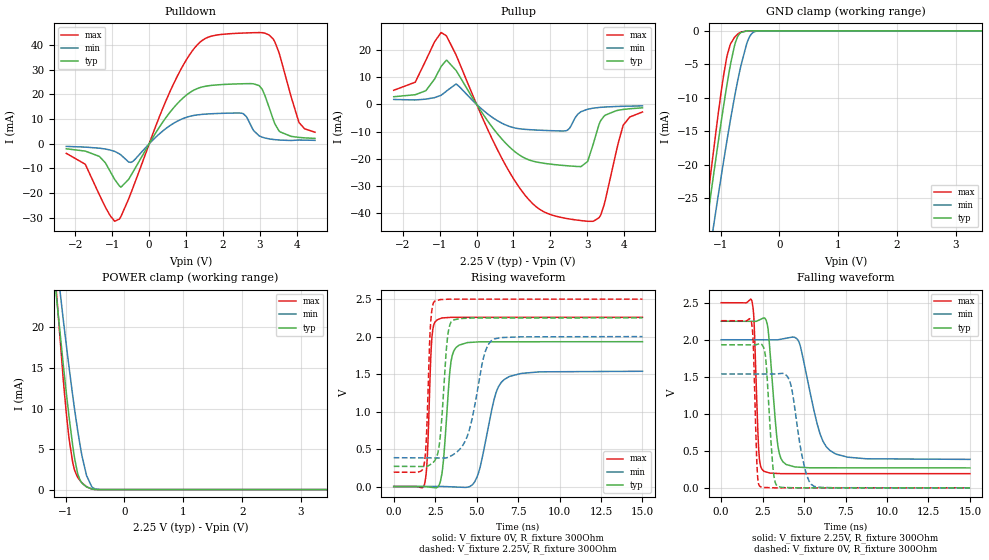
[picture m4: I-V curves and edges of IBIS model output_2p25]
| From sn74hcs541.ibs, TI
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|   output_2p25 Model
[Model]   output_2p25
Model_type   I/O
Polarity   Non-Inverting
Enable   Active-High
Vmeas = 1.125
Vref = 0
Cref = 2pF
Rref = 100000
Vinl = 0.835
Vinh = 1.2
|   typ   min   max
C_comp   0.937pF   0.886pF   0.963pF
| Where Nom  PVT is Nominal Process, 2.25V, 27C
|   Fast PVT is Strong Process,  2.50V, -55C
|   Slow PVT is Weak Process,   2.0V, 150C
[Voltage Range]   2.25   2   2.5
|Junction Temperature
[Temperature Range]   27   150   -55
[Pullup Reference]   2.25   2   2.5
[Pulldown Reference]   0   0   0
[Power Clamp Reference]   2.25   2   2.5
[GND Clamp Reference]   0   0   0
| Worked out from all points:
|   slope of the pulldown table from 0 to 0.337 V, typ, clamps not added: 41.6 ohm
|   slope of the pullup table from 0 to 0.337 V, typ, clamps not added: 49.5 ohm
|   GND clamp passes 1 mA (typ) near -0.72 V on its own axis
|   POWER clamp passes 1 mA (typ) near -0.74 V on its own axis
|   falling waveform, V_fixture 2.25V, R_fixture 300Ohm: 20-80 % time 427ps typ, 992ps min, 216ps max; typ from 2.25 V to 0.269 V
|   rising waveform, V_fixture 0V, R_fixture 300Ohm: 20-80 % time 377ps typ, 879ps min, 215ps max; typ from 0 V to 1.93 V
|   rising waveform, V_fixture 2.25V, R_fixture 300Ohm: 20-80 % time 379ps typ, 878ps min, 218ps max; typ from 0.269 V to 2.25 V
|   falling waveform, V_fixture 0V, R_fixture 300Ohm: 20-80 % time 325ps typ, 662ps min, 177ps max; typ from 1.93 V to 0 V
[Pulldown]
|   Voltage   I(typ)   I(min)   I(max)
-2.25V    -2.019mA   -1.051mA   -3.867mA
-1.737V   -2.956mA   -1.338mA   -8.261mA
-1.352V   -5.109mA   -1.777mA   -20.65mA
-805.5mV  -17.13mA   -4.093mA   -30.48mA
-461.2mV  -11.99mA   -7.313mA   -18.63mA
949.5mV   18.99mA    10.42mA    32.57mA
2.057V    24.09mA    12.39mA    44.49mA
2.556V    24.35mA    12.19mA    44.91mA
2.981V    23.61mA    3.258mA    45.1mA
3.359V    10.14mA    1.771mA    42.63mA
4.061V    2.596mA    1.53mA     8.818mA
4.5V      2.197mA    1.398mA    4.702mA
[GND Clamp]
|   Voltage   I(typ)   I(min)   I(max)
-2.25V    -97.51mA   -98.31mA   -106.7mA
-1.413V   -40.56mA   -46.57mA   -39.9mA
-1.17V    -24.74mA   -32.11mA   -21.56mA
-1.157V   -23.88mA   -31.32mA   -20.58mA
-1.048V   -17.16mA   -25.09mA   -13.01mA
-954mV    -11.56mA   -19.8mA    -7.02mA
-886.5mV  -7.821mA   -16.15mA   -3.647mA
-758.2mV  -2.094mA   -9.706mA   -933.8uA
-650.2mV  -236.3uA   -5.079mA   -178.5uA
-515.2mV  -9.553uA   -1.047mA   -5.579uA
-373.5mV  -159.7nA   -38.68uA   -18.72nA
4.5V      0A         0A         0A
[Pullup]
|   Voltage   I(typ)   I(min)   I(max)
-2.25V    2.824mA    1.819mA    5.194mA
-1.669V   3.557mA    1.632mA    8.15mA
-1.379V   5.027mA    1.94mA     16.19mA
-825.7mV  16.2mA     4.794mA    25.31mA
-555.7mV  12.46mA    7.533mA    18.14mA
463.5mV   -9.106mA   -5.134mA   -13.92mA
1.253V    -19.4mA    -9.115mA   -32.38mA
2.434V    -22.56mA   -9.668mA   -41.98mA
3.015V    -20.85mA   -1.762mA   -43.03mA
3.454V    -4.395mA   -992.6uA   -37.21mA
3.974V    -1.87mA    -692.2uA   -7.807mA
4.5V      -1.267mA   -550uA     -2.795mA
[POWER Clamp]
|   Voltage   I(typ)   I(min)   I(max)
-2.25V    111.3mA    101.8mA    143.6mA
-1.305V   34.66mA    37.92mA    38.3mA
-1.042V   15.57mA    21.11mA    13.76mA
-987.8mV  11.94mA    17.84mA    9.441mA
-940.5mV  8.946mA    15.06mA    6.255mA
-879.8mV  5.467mA    11.64mA    3.383mA
-792mV    1.914mA    7.17mA     1.486mA
-717.7mV  771.2uA    4.03mA     811.5uA
-643.5mV  332.5uA    1.729mA    341.9uA
-555.7mV  82.38uA    359.8uA    63.02uA
-420.8mV  3.273uA    16.09uA    933.6nA
4.5V      0A         0A         0A
[Ramp]
R_load = 300
|   typ   min   max
dV/dt_r   1.15931/3.7709e-10   0.922472/8.75361e-10   1.3543/2.14529e-10
dV/dt_f   1.18843/4.26313e-10   0.96929/9.90291e-10   1.38516/2.1601e-10
[Falling Waveform]
V_fixture = 2.25V
V_fixture_min = 2V
V_fixture_max = 2.5V
R_fixture = 300Ohm
C_fixture = 0F
|   Time   V(typ)   V(min)   V(max)
0s        2.25V      2V         2.5V
1.848ns   2.249V     1.999V     2.525V
2.28ns    2.265V     1.999V     459.5mV
2.571ns   2.296V     1.999V     225.4mV
2.827ns   2.142V     1.999V     206.9mV
3.431ns   551.5mV    2V         194mV
3.901ns   318.6mV    2.02V      192mV
4.692ns   279.4mV    1.969V     192mV
6.54ns    270.8mV    508.5mV    191.9mV
15ns      269.3mV    384.5mV    191.4mV
[Rising Waveform]
V_fixture = 0V
V_fixture_min = 0V
V_fixture_max = 0V
R_fixture = 300Ohm
C_fixture = 0F
|   Time   V(typ)   V(min)   V(max)
0s        5.761uV    9.239uV    3.21uV
1.848ns   759.6uV    436.1uV    25.37mV
2.298ns   -11.33mV   539.9uV    1.97V
2.623ns   -10.61mV   615uV      2.224V
2.944ns   233.6mV    689uV      2.249V
3.456ns   1.666V     -3.939mV   2.257V
3.934ns   1.885V     -8.271mV   2.257V
5.028ns   1.928V     128.9mV    2.257V
6.645ns   1.931V     1.424V     2.257V
15ns      1.932V     1.537V     2.257V
[Rising Waveform]
V_fixture = 2.25V
V_fixture_min = 2V
V_fixture_max = 2.5V
R_fixture = 300Ohm
C_fixture = 0F
|   Time   V(typ)   V(min)   V(max)
0s        269.3mV    384.5mV    191.4mV
1.798ns   267.3mV    382.1mV    260.5mV
1.966ns   267.1mV    381.9mV    633mV
2.221ns   295.1mV    381.6mV    2.167V
2.465ns   342.7mV    381.2mV    2.471V
2.798ns   651mV      380.8mV    2.494V
3.262ns   2.019V     388mV      2.499V
3.559ns   2.219V     421.1mV    2.5V
6.02ns    2.249V     1.966V     2.5V
15ns      2.25V      2V         2.5V
[Falling Waveform]
|Gnd
V_fixture = 0V
V_fixture_min = 0V
V_fixture_max = 0V
R_fixture = 300Ohm
C_fixture = 0F
|   Time   V(typ)   V(min)   V(max)
0s        1.932V     1.537V     2.257V
1.821ns   1.931V     1.537V     2.245V
2.172ns   1.937V     1.537V     241.7mV
2.35ns    1.949V     1.537V     16.42mV
2.663ns   1.791V     1.537V     4.641mV
3.134ns   247.6mV    1.537V     909.1uV
3.414ns   18.76mV    1.54V      392.5uV
4.133ns   3.026mV    1.441V     368.3uV
5.589ns   659.1uV    22.58mV    319.5uV
15ns      5.97uV     9.55uV     3.344uV
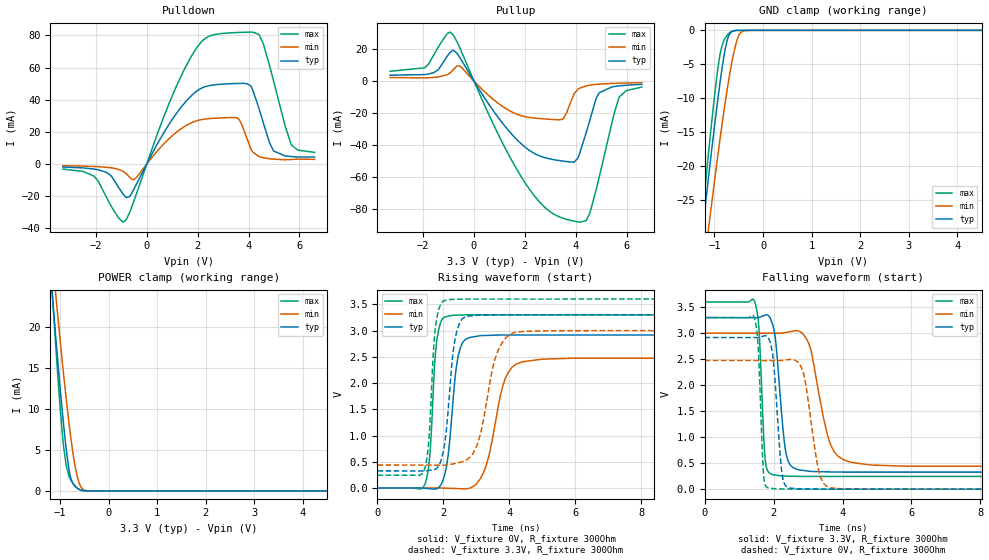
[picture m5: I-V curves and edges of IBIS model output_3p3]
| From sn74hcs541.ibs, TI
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|   output_3p3 Model
[Model]   output_3p3
Model_type   I/O
Polarity   Non-Inverting
Enable   Active-High
Vmeas = 1.65
Vref = 0
Cref = 2pF
Rref = 100000
Vinl = 1.6
Vinh = 2.3
|   typ   min   max
C_comp   0.878pF   0.839pF   0.891pF
| Where Nom  PVT is Nominal Process, 3.3V, 27C
|   Fast PVT is Strong Process,  3.6V, -55C
|   Slow PVT is Weak Process,   3.0V, 150C
[Voltage Range]   3.3   3   3.6
|Junction Temperature
[Temperature Range]   27   150   -55
[Pullup Reference]   3.3   3   3.6
[Pulldown Reference]   0   0   0
[Power Clamp Reference]   3.3   3   3.6
[GND Clamp Reference]   0   0   0
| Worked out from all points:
|   slope of the pulldown table from 0 to 0.495 V, typ, clamps not added: 33.8 ohm
|   slope of the pullup table from 0 to 0.495 V, typ, clamps not added: 39.9 ohm
|   GND clamp passes 1 mA (typ) near -0.72 V on its own axis
|   POWER clamp passes 1 mA (typ) near -0.74 V on its own axis
|   falling waveform, V_fixture 3.3V, R_fixture 300Ohm: 20-80 % time 227ps typ, 464ps min, 131ps max; typ from 3.3 V to 0.328 V
|   rising waveform, V_fixture 0V, R_fixture 300Ohm: 20-80 % time 265ps typ, 493ps min, 178ps max; typ from 0 V to 2.92 V
|   rising waveform, V_fixture 3.3V, R_fixture 300Ohm: 20-80 % time 265ps typ, 494ps min, 179ps max; typ from 0.328 V to 3.3 V
|   falling waveform, V_fixture 0V, R_fixture 300Ohm: 20-80 % time 186ps typ, 325ps min, 116ps max; typ from 2.92 V to 0 V
[Pulldown]
|   Voltage   I(typ)   I(min)   I(max)
-3.3V     -1.874mA   -1.09mA    -3.153mA
-2.072V   -3.148mA   -1.553mA   -7.616mA
-815.1mV  -20.76mA   -5.906mA   -34.91mA
-468.6mV  -14.47mA   -9.363mA   -21.34mA
1.719V    41.96mA    25.37mA    66.07mA
3.244V    49.91mA    28.86mA    81.54mA
3.66V     50.14mA    26.88mA    81.86mA
4.075V    48.79mA    10.04mA    82.07mA
4.422V    33.99mA    4.608mA    80.33mA
4.986V    8.151mA    3.011mA    51.62mA
5.679V    4.642mA    2.795mA    12.07mA
6.6V      4.33mA     2.888mA    7.224mA
[GND Clamp]
|   Voltage   I(typ)   I(min)   I(max)
-3.3V     -170.7mA   -164.8mA   -192.4mA
-1.27V    -31.2mA    -38.03mA   -29.01mA
-1.122V   -21.71mA   -29.31mA   -18.11mA
-1.073V   -18.63mA   -26.46mA   -14.64mA
-983.4mV  -13.27mA   -21.43mA   -8.78mA
-894.3mV  -8.237mA   -16.57mA   -3.969mA
-815.1mV  -4.303mA   -12.46mA   -1.69mA
-755.7mV  -2.013mA   -9.587mA   -907.2uA
-636.9mV  -174.3uA   -4.574mA   -135.1uA
-498.3mV  -6.151uA   -766.4uA   -3.251uA
-339.9mV  -43.96nA   -15.79uA   0A
6.6V      0A         0A         0A
[Pullup]
|   Voltage   I(typ)   I(min)   I(max)
-3.3V     3.687mA    2.24mA     6.129mA
-1.934V   4.09mA     2.002mA    8.387mA
-943.8mV  17.91mA    5.04mA     30.66mA
-557.7mV  14.76mA    9.463mA    20.86mA
927.3mV   -22.25mA   -13.6mA    -32.5mA
2.086V    -42.26mA   -22.51mA   -65.45mA
3.472V    -50.02mA   -23.91mA   -85.67mA
4.155V    -45.23mA   -4.427mA   -88.3mA
4.551V    -24.71mA   -2.556mA   -82.73mA
4.867V    -8.715mA   -1.979mA   -63.8mA
5.699V    -3.005mA   -1.33mA    -10.31mA
6.6V      -2.065mA   -1.063mA   -3.741mA
[POWER Clamp]
|   Voltage   I(typ)   I(min)   I(max)
-3.3V     211.7mA    184.7mA    283.2mA
-1.152V   23.34mA    28mA       23.6mA
-1.073V   17.7mA     23.01mA    16.41mA
-993.3mV  12.31mA    18.17mA    9.859mA
-943.8mV  9.149mA    15.25mA    6.453mA
-874.5mV  5.196mA    11.36mA    3.199mA
-815.1mV  2.61mA     8.282mA    1.781mA
-765.6mV  1.349mA    5.972mA    1.216mA
-666.6mV  440uA      2.342mA    466.4uA
-577.5mV  123.3uA    563.4uA    104.5uA
-290.4mV  398.2nA    738.5nA    0A
6.6V      0A         0A         0A
[Ramp]
R_load = 300
|   typ   min   max
dV/dt_r   1.74981/2.62998e-10   1.48539/4.87639e-10   1.9797/1.77055e-10
dV/dt_f   1.78348/2.27314e-10   1.53673/4.63991e-10   2.013/1.30288e-10
[Falling Waveform]
V_fixture = 3.3V
V_fixture_min = 3V
V_fixture_max = 3.6V
R_fixture = 300Ohm
C_fixture = 0F
|   Time   V(typ)   V(min)   V(max)
0s        3.3V       3V         3.6V
1.449ns   3.298V     2.999V     3.609V
1.573ns   3.303V     2.999V     3.109V
1.758ns   3.347V     2.999V     554.7mV
1.959ns   3.189V     2.999V     281.1mV
2.355ns   706.5mV    3.014V     251.6mV
2.682ns   379mV      3.047V     246.8mV
3.663ns   331.4mV    842.4mV    245.5mV
4.224ns   328.6mV    519.7mV    245.5mV
15ns      327.5mV    438.8mV    245mV
[Rising Waveform]
V_fixture = 0V
V_fixture_min = 0V
V_fixture_max = 0V
R_fixture = 300Ohm
C_fixture = 0F
|   Time   V(typ)   V(min)   V(max)
0s        6.739uV    10.26uV    3.594uV
1.436ns   -4.159mV   720.3uV    70.57mV
1.59ns    -12.54mV   796.4uV    647.7mV
1.796ns   -12.7mV    898.1uV    2.796V
2.066ns   327.8mV    -2.078mV   3.263V
2.438ns   2.485V     -10.21mV   3.294V
2.782ns   2.866V     -4.546mV   3.299V
3.884ns   2.915V     2.096V     3.299V
4.38ns    2.915V     2.403V     3.299V
15ns      2.916V     2.476V     3.3V
[Rising Waveform]
V_fixture = 3.3V
V_fixture_min = 3V
V_fixture_max = 3.6V
R_fixture = 300Ohm
C_fixture = 0F
|   Time   V(typ)   V(min)   V(max)
0s        327.5mV    438.8mV    245mV
1.413ns   325mV      437.6mV    334.2mV
1.562ns   336.3mV    437.5mV    952.9mV
1.752ns   356.4mV    437.3mV    3.029V
2.012ns   749.1mV    437.1mV    3.57V
2.35ns    2.828V     469.4mV    3.595V
2.674ns   3.267V     526.7mV    3.6V
3.625ns   3.299V     2.574V     3.6V
4.156ns   3.299V     2.965V     3.6V
15ns      3.3V       3V         3.6V
[Falling Waveform]
|Gnd
V_fixture = 0V
V_fixture_min = 0V
V_fixture_max = 0V
R_fixture = 300Ohm
C_fixture = 0F
|   Time   V(typ)   V(min)   V(max)
0s        2.916V     2.476V     3.3V
1.436ns   2.915V     2.475V     3.301V
1.552ns   2.916V     2.475V     2.742V
1.709ns   2.944V     2.475V     274mV
1.844ns   2.912V     2.475V     23.14mV
2.241ns   314.3mV    2.478V     3.738mV
2.445ns   24.52mV    2.493V     1.817mV
2.859ns   5.535mV    2.243V     310.2uV
3.637ns   619.7uV    27.93mV    290.5uV
15ns      6.964uV    10.56uV    3.715uV
